VERSION 5.7 ;
  NOWIREEXTENSIONATPIN ON ;
  DIVIDERCHAR "/" ;
  BUSBITCHARS "[]" ;
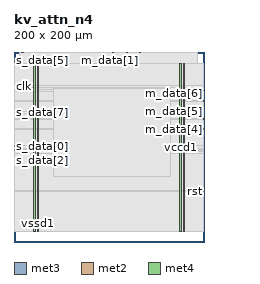
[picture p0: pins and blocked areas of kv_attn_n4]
MACRO kv_attn_n4
  CLASS BLOCK ;
  FOREIGN kv_attn_n4 ;
  ORIGIN 0.000 0.000 ;
  SIZE 200.000 BY 200.000 ;
  PIN clk
    DIRECTION INPUT ;
    USE SIGNAL ;
    ANTENNAGATEAREA 1.286700 ;
    ANTENNADIFFAREA 0.434700 ;
    PORT
      LAYER met3 ;
        RECT 0.000 163.240 0.600 163.840 ;
    END
  END clk
  PIN m_data[0]
    DIRECTION OUTPUT ;
    USE SIGNAL ;
    ANTENNADIFFAREA 0.702900 ;
    PORT
      LAYER met2 ;
        RECT 99.450 199.720 99.730 200.000 ;
    END
  END m_data[0]
  PIN m_data[1]
    DIRECTION OUTPUT ;
    USE SIGNAL ;
    ANTENNADIFFAREA 0.702900 ;
    PORT
      LAYER met2 ;
        RECT 101.290 199.720 101.570 200.000 ;
    END
  END m_data[1]
  PIN m_data[2]
    DIRECTION OUTPUT ;
    USE SIGNAL ;
    ANTENNADIFFAREA 0.702900 ;
    PORT
      LAYER met2 ;
        RECT 104.050 199.720 104.330 200.000 ;
    END
  END m_data[2]
  PIN m_data[3]
    DIRECTION OUTPUT ;
    USE SIGNAL ;
    ANTENNADIFFAREA 0.702900 ;
    PORT
      LAYER met2 ;
        RECT 153.730 199.720 154.010 200.000 ;
    END
  END m_data[3]
  PIN m_data[4]
    DIRECTION OUTPUT ;
    USE SIGNAL ;
    ANTENNADIFFAREA 0.702900 ;
    PORT
      LAYER met3 ;
        RECT 199.400 118.360 200.000 118.960 ;
    END
  END m_data[4]
  PIN m_data[5]
    DIRECTION OUTPUT ;
    USE SIGNAL ;
    ANTENNADIFFAREA 0.702900 ;
    PORT
      LAYER met3 ;
        RECT 199.400 129.240 200.000 129.840 ;
    END
  END m_data[5]
  PIN m_data[6]
    DIRECTION OUTPUT ;
    USE SIGNAL ;
    ANTENNADIFFAREA 0.702900 ;
    PORT
      LAYER met3 ;
        RECT 199.400 148.280 200.000 148.880 ;
    END
  END m_data[6]
  PIN m_data[7]
    DIRECTION OUTPUT ;
    USE SIGNAL ;
    ANTENNADIFFAREA 0.702900 ;
    PORT
      LAYER met3 ;
        RECT 199.400 159.160 200.000 159.760 ;
    END
  END m_data[7]
  PIN m_last
    DIRECTION OUTPUT ;
    USE SIGNAL ;
    ANTENNADIFFAREA 0.702900 ;
    PORT
      LAYER met2 ;
        RECT 132.570 199.720 132.850 200.000 ;
    END
  END m_last
  PIN m_ready
    DIRECTION INPUT ;
    USE SIGNAL ;
    ANTENNAGATEAREA 0.647700 ;
    ANTENNADIFFAREA 0.434700 ;
    PORT
      LAYER met2 ;
        RECT 118.770 199.720 119.050 200.000 ;
    END
  END m_ready
  PIN m_valid
    DIRECTION OUTPUT ;
    USE SIGNAL ;
    ANTENNADIFFAREA 0.702900 ;
    PORT
      LAYER met2 ;
        RECT 119.690 199.720 119.970 200.000 ;
    END
  END m_valid
  PIN rst
    DIRECTION INPUT ;
    USE SIGNAL ;
    ANTENNAGATEAREA 0.647700 ;
    ANTENNADIFFAREA 0.434700 ;
    PORT
      LAYER met3 ;
        RECT 199.400 53.080 200.000 53.680 ;
    END
  END rst
  PIN s_data[0]
    DIRECTION INPUT ;
    USE SIGNAL ;
    ANTENNAGATEAREA 0.647700 ;
    ANTENNADIFFAREA 0.434700 ;
    PORT
      LAYER met3 ;
        RECT 0.000 100.680 0.600 101.280 ;
    END
  END s_data[0]
  PIN s_data[1]
    DIRECTION INPUT ;
    USE SIGNAL ;
    ANTENNAGATEAREA 0.647700 ;
    ANTENNADIFFAREA 0.434700 ;
    PORT
      LAYER met3 ;
        RECT 0.000 99.320 0.600 99.920 ;
    END
  END s_data[1]
  PIN s_data[2]
    DIRECTION INPUT ;
    USE SIGNAL ;
    ANTENNAGATEAREA 0.647700 ;
    ANTENNADIFFAREA 0.434700 ;
    PORT
      LAYER met3 ;
        RECT 0.000 93.880 0.600 94.480 ;
    END
  END s_data[2]
  PIN s_data[3]
    DIRECTION INPUT ;
    USE SIGNAL ;
    ANTENNAGATEAREA 0.647700 ;
    ANTENNADIFFAREA 0.434700 ;
    PORT
      LAYER met3 ;
        RECT 0.000 96.600 0.600 97.200 ;
    END
  END s_data[3]
  PIN s_data[4]
    DIRECTION INPUT ;
    USE SIGNAL ;
    ANTENNAGATEAREA 0.647700 ;
    ANTENNADIFFAREA 0.434700 ;
    PORT
      LAYER met2 ;
        RECT 8.370 199.720 8.650 200.000 ;
    END
  END s_data[4]
  PIN s_data[5]
    DIRECTION INPUT ;
    USE SIGNAL ;
    ANTENNAGATEAREA 0.647700 ;
    ANTENNADIFFAREA 0.434700 ;
    PORT
      LAYER met2 ;
        RECT 12.050 199.720 12.330 200.000 ;
    END
  END s_data[5]
  PIN s_data[6]
    DIRECTION INPUT ;
    USE SIGNAL ;
    ANTENNAGATEAREA 0.647700 ;
    ANTENNADIFFAREA 0.434700 ;
    PORT
      LAYER met2 ;
        RECT 10.210 199.720 10.490 200.000 ;
    END
  END s_data[6]
  PIN s_data[7]
    DIRECTION INPUT ;
    USE SIGNAL ;
    ANTENNAGATEAREA 0.647700 ;
    ANTENNADIFFAREA 0.434700 ;
    PORT
      LAYER met3 ;
        RECT 0.000 136.040 0.600 136.640 ;
    END
  END s_data[7]
  PIN s_last
    DIRECTION INPUT ;
    USE SIGNAL ;
    ANTENNAGATEAREA 0.647700 ;
    ANTENNADIFFAREA 0.434700 ;
    PORT
      LAYER met2 ;
        RECT 11.130 199.720 11.410 200.000 ;
    END
  END s_last
  PIN s_ready
    DIRECTION OUTPUT ;
    USE SIGNAL ;
    ANTENNADIFFAREA 0.702900 ;
    PORT
      LAYER met2 ;
        RECT 12.970 199.720 13.250 200.000 ;
    END
  END s_ready
  PIN s_valid
    DIRECTION INPUT ;
    USE SIGNAL ;
    ANTENNAGATEAREA 0.647700 ;
    ANTENNADIFFAREA 0.434700 ;
    PORT
      LAYER met2 ;
        RECT 9.290 199.720 9.570 200.000 ;
    END
  END s_valid
  PIN vccd1
    DIRECTION INOUT ;
    USE POWER ;
    PORT
      LAYER met4 ;
        RECT 21.040 10.640 22.640 187.920 ;
    END
    PORT
      LAYER met4 ;
        RECT 174.640 10.640 176.240 187.920 ;
    END
  END vccd1
  PIN vssd1
    DIRECTION INOUT ;
    USE GROUND ;
    PORT
      LAYER met4 ;
        RECT 24.340 10.640 25.940 187.920 ;
    END
    PORT
      LAYER met4 ;
        RECT 177.940 10.640 179.540 187.920 ;
    END
  END vssd1
  OBS
      LAYER nwell ;
        RECT 5.330 10.795 194.310 187.870 ;
      LAYER li1 ;
        RECT 5.520 10.795 194.120 187.765 ;
      LAYER met1 ;
        RECT 5.520 10.640 194.420 187.920 ;
      LAYER met2 ;
        RECT 5.610 199.440 8.090 199.720 ;
        RECT 8.930 199.440 9.010 199.720 ;
        RECT 9.850 199.440 9.930 199.720 ;
        RECT 10.770 199.440 10.850 199.720 ;
        RECT 11.690 199.440 11.770 199.720 ;
        RECT 12.610 199.440 12.690 199.720 ;
        RECT 13.530 199.440 99.170 199.720 ;
        RECT 100.010 199.440 101.010 199.720 ;
        RECT 101.850 199.440 103.770 199.720 ;
        RECT 104.610 199.440 118.490 199.720 ;
        RECT 119.330 199.440 119.410 199.720 ;
        RECT 120.250 199.440 132.290 199.720 ;
        RECT 133.130 199.440 153.450 199.720 ;
        RECT 154.290 199.440 192.650 199.720 ;
        RECT 5.610 10.695 192.650 199.440 ;
      LAYER met3 ;
        RECT 0.600 164.240 199.400 187.845 ;
        RECT 1.000 162.840 199.400 164.240 ;
        RECT 0.600 160.160 199.400 162.840 ;
        RECT 0.600 158.760 199.000 160.160 ;
        RECT 0.600 149.280 199.400 158.760 ;
        RECT 0.600 147.880 199.000 149.280 ;
        RECT 0.600 137.040 199.400 147.880 ;
        RECT 1.000 135.640 199.400 137.040 ;
        RECT 0.600 130.240 199.400 135.640 ;
        RECT 0.600 128.840 199.000 130.240 ;
        RECT 0.600 119.360 199.400 128.840 ;
        RECT 0.600 117.960 199.000 119.360 ;
        RECT 0.600 101.680 199.400 117.960 ;
        RECT 1.000 98.920 199.400 101.680 ;
        RECT 0.600 97.600 199.400 98.920 ;
        RECT 1.000 96.200 199.400 97.600 ;
        RECT 0.600 94.880 199.400 96.200 ;
        RECT 1.000 93.480 199.400 94.880 ;
        RECT 0.600 54.080 199.400 93.480 ;
        RECT 0.600 52.680 199.000 54.080 ;
        RECT 0.600 10.715 199.400 52.680 ;
      LAYER met4 ;
        RECT 41.695 68.855 164.385 161.665 ;
  END
END kv_attn_n4
END LIBRARY

